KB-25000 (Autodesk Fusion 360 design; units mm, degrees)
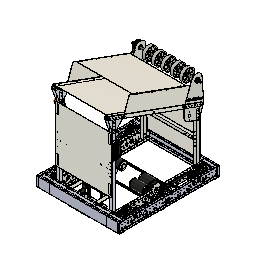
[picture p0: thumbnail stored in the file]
description: STEP AP214
part number: KB-25000
description: Part Number
part number: 10-32x0500_shcs_HX-SHCS 0.19-32x1.375x1-C.STEP
part number: 10-32 Nylock Nut 1_90631A411.STEP
part number: am-1002 and am-1042 10-32 x 0500 and Nylock Nut Assembly.STEP
part number: am-3920 AM14U6 End Plate Long Centered Cut.STEP
part number: am-3921b AM14U5 On Grid Outside Plate_Long Configuration.STEP
part number: am-3922b AM14U6 Inside Plate_Long Configuration.STEP
part number: 3.375in Churro.STEP
part number: 18.50in Churro.STEP
part number: FHTS 0.25-20-0.75_FHTS 0.25-20-G-0.75-C.STEP
base_feature "Base Feature1"
base_feature "Base Feature1"
base_feature "Base Feature1"
base_feature "Base Feature1"
base_feature "Base Feature1"
base_feature "Base Feature1"
base_feature "Base Feature1"
base_feature "Base Feature1"
base_feature "Base Feature1"
base_feature "Base Feature1"
base_feature "Base Feature1"
base_feature "Base Feature1"
base_feature "Base Feature1"
base_feature "Base Feature1"
base_feature "Base Feature1"
base_feature "Base Feature1"
base_feature "Base Feature1"
base_feature "Base Feature1"
base_feature "Base Feature1"
base_feature "Base Feature1"
base_feature "Base Feature1"
base_feature "Base Feature1"
base_feature "Base Feature1"
base_feature "Base Feature1"
base_feature "Base Feature1"
base_feature "Base Feature1"
base_feature "Base Feature1"
base_feature "Base Feature1"
base_feature "Base Feature1"
base_feature "Base Feature1"
base_feature "Base Feature1"
base_feature "Base Feature1"
base_feature "Base Feature1"
base_feature "Base Feature1"
base_feature "Base Feature1"
base_feature "Base Feature1"
base_feature "Base Feature1"
base_feature "Base Feature1"
base_feature "Base Feature1"
base_feature "Base Feature1"
base_feature "Base Feature1"
base_feature "Base Feature1"
base_feature "Base Feature1"
base_feature "Base Feature1"
base_feature "Base Feature1"
base_feature "Base Feature1"
base_feature "Base Feature1"
base_feature "Base Feature1"
base_feature "Base Feature1"
base_feature "Base Feature1"
base_feature "Base Feature1"
base_feature "Base Feature1"
base_feature "Base Feature1"
base_feature "Base Feature1"
base_feature "Base Feature1"
base_feature "Base Feature1"
base_feature "Base Feature1"
base_feature "Base Feature1"
base_feature "Base Feature1"
base_feature "Base Feature1"
base_feature "Base Feature1"
base_feature "Base Feature1"
base_feature "Base Feature1"
base_feature "Base Feature1"
base_feature "Base Feature1"
base_feature "Base Feature1"
base_feature "Base Feature1"
base_feature "Base Feature1"
base_feature "Base Feature1"
base_feature "Base Feature1"
base_feature "Base Feature1"
base_feature "Base Feature1"
base_feature "Base Feature1"
base_feature "Base Feature1"
base_feature "Base Feature1"
base_feature "Base Feature1"
base_feature "Base Feature1"
base_feature "Base Feature1"
base_feature "Base Feature1"
base_feature "Base Feature1"
base_feature "Base Feature1"
base_feature "Base Feature1"
base_feature "Base Feature1"
base_feature "Base Feature1"
base_feature "Base Feature1"
base_feature "Base Feature1"
base_feature "Base Feature1"
base_feature "Base Feature1"
base_feature "Base Feature1"
base_feature "Base Feature1"
base_feature "Base Feature1"
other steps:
create_component "CreateComponent1"
create_component "CreateComponent1"
create_component "CreateComponent1"
create_component "CreateComponent1"
create_component "CreateComponent1"
create_component "CreateComponent1"
create_component "CreateComponent2"
create_component "CreateComponent2"
create_component "CreateComponent3"
create_component "CreateComponent4"
create_component "CreateComponent5"
create_component "CreateComponent6"
create_component "CreateComponent7"
create_component "CreateComponent2"
create_component "CreateComponent1"
create_component "CreateComponent1"
create_component "CreateComponent2"
create_component "CreateComponent2"
create_component "CreateComponent3"
create_component "CreateComponent4"
create_component "CreateComponent5"
create_component "CreateComponent6"
create_component "CreateComponent3"
create_component "CreateComponent1"
create_component "CreateComponent2"
create_component "CreateComponent4"
create_component "CreateComponent1"
create_component "CreateComponent1"
create_component "CreateComponent1"
create_component "CreateComponent1"
create_component "CreateComponent2"
create_component "CreateComponent3"
create_component "CreateComponent4"
create_component "CreateComponent5"
create_component "CreateComponent6"
create_component "CreateComponent7"
create_component "CreateComponent2"
create_component "CreateComponent1"
create_component "CreateComponent2"
create_component "CreateComponent3"
create_component "CreateComponent2"
create_component "CreateComponent3"
create_component "CreateComponent4"
create_component "CreateComponent2"
create_component "CreateComponent1"
create_component "CreateComponent2"
create_component "CreateComponent3"
create_component "CreateComponent4"
create_component "CreateComponent5"
create_component "CreateComponent6"
create_component "CreateComponent5"
create_component "CreateComponent6"
create_component "CreateComponent7"
create_component "CreateComponent8"
create_component "CreateComponent2"
create_component "CreateComponent1"
create_component "CreateComponent1"
create_component "CreateComponent2"
create_component "CreateComponent3"
create_component "CreateComponent4"
create_component "CreateComponent5"
create_component "CreateComponent6"
create_component "CreateComponent7"
create_component "CreateComponent8"
create_component "CreateComponent9"
create_component "CreateComponent10"
create_component "CreateComponent3"
create_component "CreateComponent4"
create_component "CreateComponent5"
create_component "CreateComponent6"
create_component "CreateComponent7"
create_component "CreateComponent8"
create_component "CreateComponent9"
create_component "CreateComponent10"
create_component "CreateComponent11"
create_component "CreateComponent12"
create_component "CreateComponent13"
create_component "CreateComponent14"
create_component "CreateComponent15"
create_component "CreateComponent16"
create_component "CreateComponent17"
create_component "CreateComponent18"
create_component "CreateComponent19"
create_component "CreateComponent20"
create_component "CreateComponent21"
create_component "CreateComponent22"
create_component "CreateComponent23"
create_component "CreateComponent24"
create_component "CreateComponent25"
create_component "CreateComponent26"
create_component "CreateComponent27"
create_component "CreateComponent28"
create_component "CreateComponent29"
create_component "CreateComponent30"
create_component "CreateComponent31"
create_component "CreateComponent32"
create_component "CreateComponent1"
create_component "CreateComponent1"
create_component "CreateComponent2"
create_component "CreateComponent33"
create_component "CreateComponent34"
create_component "CreateComponent35"
create_component "CreateComponent36"
create_component "CreateComponent37"
create_component "CreateComponent38"
create_component "CreateComponent39"
create_component "CreateComponent40"
create_component "CreateComponent41"
create_component "CreateComponent42"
